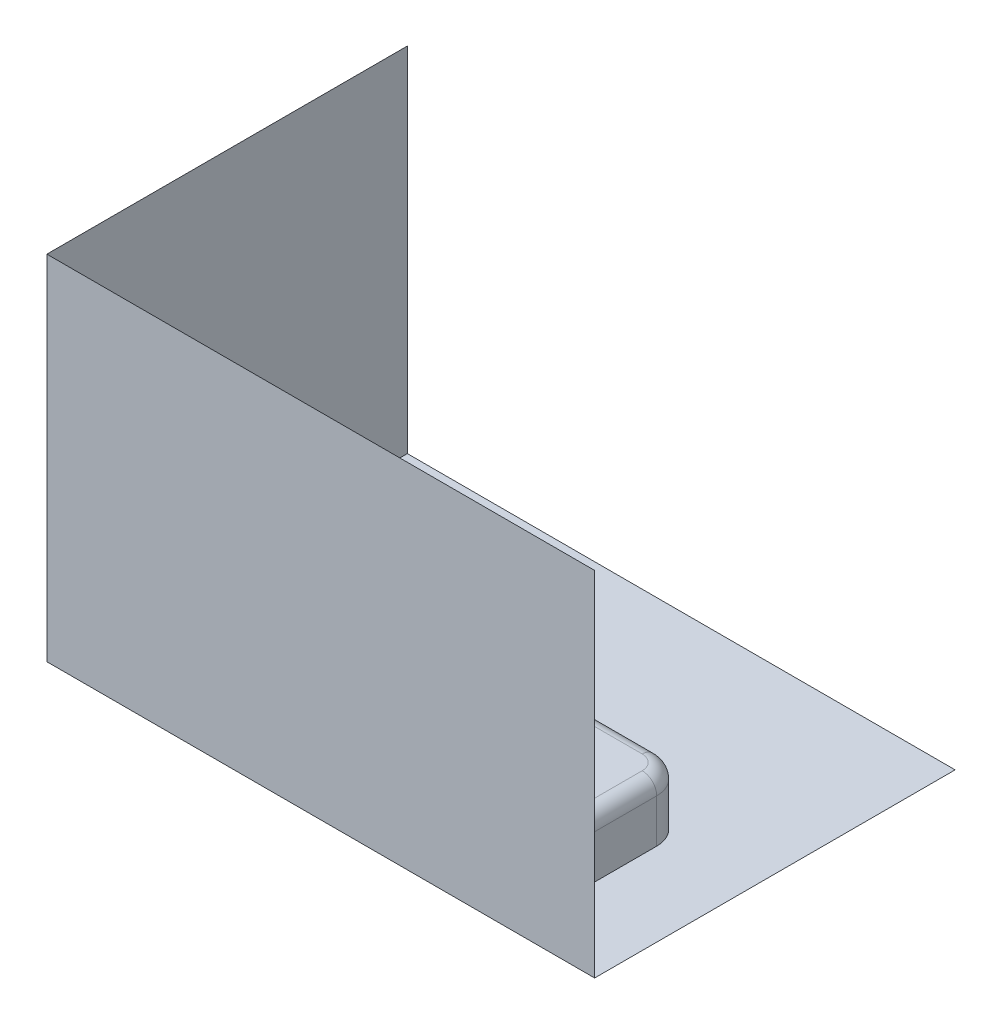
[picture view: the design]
ISO-10303-21;
HEADER;
FILE_DESCRIPTION(('STEP AP214'),'2;1');
FILE_NAME('part.step','',(''),(''),'','','');
FILE_SCHEMA(('AUTOMOTIVE_DESIGN { 1 0 10303 214 1 1 1 1 }'));
ENDSEC;
DATA;
#1=APPLICATION_CONTEXT('core data for automotive mechanical design processes');
#2=APPLICATION_PROTOCOL_DEFINITION('international standard','automotive_design',2000,#1);
#3=PRODUCT_CONTEXT('',#1,'mechanical');
#4=PRODUCT('Part','Part','',(#3));
#5=PRODUCT_RELATED_PRODUCT_CATEGORY('part','',(#4));
#6=PRODUCT_DEFINITION_FORMATION('','',#4);
#7=PRODUCT_DEFINITION_CONTEXT('part definition',#1,'design');
#8=PRODUCT_DEFINITION('design','',#6,#7);
#9=PRODUCT_DEFINITION_SHAPE('','',#8);
#10=(LENGTH_UNIT() NAMED_UNIT(*) SI_UNIT(.MILLI.,.METRE.));
#11=(NAMED_UNIT(*) PLANE_ANGLE_UNIT() SI_UNIT($,.RADIAN.));
#12=(NAMED_UNIT(*) SI_UNIT($,.STERADIAN.) SOLID_ANGLE_UNIT());
#13=UNCERTAINTY_MEASURE_WITH_UNIT(LENGTH_MEASURE(1.E-05),#10,'distance_accuracy_value','');
#14=(GEOMETRIC_REPRESENTATION_CONTEXT(3) GLOBAL_UNCERTAINTY_ASSIGNED_CONTEXT((#13)) GLOBAL_UNIT_ASSIGNED_CONTEXT((#10,
#11,#12)) REPRESENTATION_CONTEXT('',''));
#15=CARTESIAN_POINT('',(0.,0.,0.));
#16=DIRECTION('',(0.,0.,1.));
#17=DIRECTION('',(1.,0.,0.));
#18=AXIS2_PLACEMENT_3D('',#15,#16,#17);
#19=CARTESIAN_POINT('',(0.,0.,0.));
#20=DIRECTION('',(0.,-1.,0.));
#21=DIRECTION('',(0.,0.,-1.));
#22=AXIS2_PLACEMENT_3D('',#19,#20,#21);
#23=PLANE('',#22);
#24=DIRECTION('',(0.,0.,-1.));
#25=VECTOR('',#24,1.);
#26=CARTESIAN_POINT('',(0.,0.,0.));
#27=LINE('',#26,#25);
#28=CARTESIAN_POINT('',(0.,0.,0.));
#29=VERTEX_POINT('',#28);
#30=CARTESIAN_POINT('',(0.,0.,-78.8265915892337));
#31=VERTEX_POINT('',#30);
#32=EDGE_CURVE('E72',#29,#31,#27,.T.);
#33=ORIENTED_EDGE('',*,*,#32,.T.);
#34=DIRECTION('',(1.,0.,0.));
#35=VECTOR('',#34,1.);
#36=CARTESIAN_POINT('',(0.,0.,-78.8265915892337));
#37=LINE('',#36,#35);
#38=CARTESIAN_POINT('',(119.774346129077,0.,-78.8265915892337));
#39=VERTEX_POINT('',#38);
#40=EDGE_CURVE('E81',#31,#39,#37,.T.);
#41=ORIENTED_EDGE('',*,*,#40,.T.);
#42=DIRECTION('',(0.,0.,1.));
#43=VECTOR('',#42,1.);
#44=CARTESIAN_POINT('',(119.774346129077,0.,0.));
#45=LINE('',#44,#43);
#46=CARTESIAN_POINT('',(119.774346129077,0.,0.));
#47=VERTEX_POINT('',#46);
#48=EDGE_CURVE('E69',#39,#47,#45,.T.);
#49=ORIENTED_EDGE('',*,*,#48,.T.);
#50=DIRECTION('',(-1.,0.,0.));
#51=VECTOR('',#50,1.);
#52=CARTESIAN_POINT('',(0.,0.,0.));
#53=LINE('',#52,#51);
#54=EDGE_CURVE('E12',#47,#29,#53,.T.);
#55=ORIENTED_EDGE('',*,*,#54,.T.);
#56=EDGE_LOOP('',(#33,#41,#49,#55));
#57=FACE_BOUND('',#56,.T.);
#58=ADVANCED_FACE('F61',(#57),#23,.T.);
#59=OPEN_SHELL('',(#58));
#60=SHELL_BASED_SURFACE_MODEL('B2',(#59));
#61=CARTESIAN_POINT('',(0.,0.,-78.8265915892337));
#62=DIRECTION('',(-1.,0.,0.));
#63=DIRECTION('',(0.,0.,1.));
#64=AXIS2_PLACEMENT_3D('',#61,#62,#63);
#65=PLANE('',#64);
#66=DIRECTION('',(0.,-1.,0.));
#67=VECTOR('',#66,1.);
#68=CARTESIAN_POINT('',(0.,77.180854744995,-78.8265915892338));
#69=LINE('',#68,#67);
#70=CARTESIAN_POINT('',(0.,77.180854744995,-78.8265915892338));
#71=VERTEX_POINT('',#70);
#72=CARTESIAN_POINT('',(0.,0.,-78.8265915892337));
#73=VERTEX_POINT('',#72);
#74=EDGE_CURVE('E128',#71,#73,#69,.T.);
#75=ORIENTED_EDGE('',*,*,#74,.T.);
#76=DIRECTION('',(0.,0.,1.));
#77=VECTOR('',#76,1.);
#78=CARTESIAN_POINT('',(0.,0.,-78.8265915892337));
#79=LINE('',#78,#77);
#80=CARTESIAN_POINT('',(0.,0.,0.));
#81=VERTEX_POINT('',#80);
#82=EDGE_CURVE('E136',#73,#81,#79,.T.);
#83=ORIENTED_EDGE('',*,*,#82,.T.);
#84=DIRECTION('',(0.,1.,0.));
#85=VECTOR('',#84,1.);
#86=CARTESIAN_POINT('',(0.,77.180854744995,0.));
#87=LINE('',#86,#85);
#88=CARTESIAN_POINT('',(0.,77.180854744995,0.));
#89=VERTEX_POINT('',#88);
#90=EDGE_CURVE('E123',#81,#89,#87,.T.);
#91=ORIENTED_EDGE('',*,*,#90,.T.);
#92=DIRECTION('',(0.,0.,-1.));
#93=VECTOR('',#92,1.);
#94=CARTESIAN_POINT('',(0.,77.180854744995,-78.8265915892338));
#95=LINE('',#94,#93);
#96=EDGE_CURVE('E58',#89,#71,#95,.T.);
#97=ORIENTED_EDGE('',*,*,#96,.T.);
#98=EDGE_LOOP('',(#75,#83,#91,#97));
#99=FACE_BOUND('',#98,.T.);
#100=ADVANCED_FACE('F119',(#99),#65,.T.);
#101=OPEN_SHELL('',(#100));
#102=SHELL_BASED_SURFACE_MODEL('B6',(#101));
#103=CARTESIAN_POINT('',(0.,0.,0.));
#104=DIRECTION('',(0.,0.,1.));
#105=DIRECTION('',(1.,0.,0.));
#106=AXIS2_PLACEMENT_3D('',#103,#104,#105);
#107=PLANE('',#106);
#108=DIRECTION('',(0.,1.,0.));
#109=VECTOR('',#108,1.);
#110=CARTESIAN_POINT('',(0.,77.180854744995,0.));
#111=LINE('',#110,#109);
#112=CARTESIAN_POINT('',(0.,0.,0.));
#113=VERTEX_POINT('',#112);
#114=CARTESIAN_POINT('',(0.,77.180854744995,0.));
#115=VERTEX_POINT('',#114);
#116=EDGE_CURVE('E187',#113,#115,#111,.T.);
#117=ORIENTED_EDGE('',*,*,#116,.T.);
#118=DIRECTION('',(1.,0.,0.));
#119=VECTOR('',#118,1.);
#120=CARTESIAN_POINT('',(0.,77.180854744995,0.));
#121=LINE('',#120,#119);
#122=CARTESIAN_POINT('',(119.774346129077,77.180854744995,0.));
#123=VERTEX_POINT('',#122);
#124=EDGE_CURVE('E199',#115,#123,#121,.T.);
#125=ORIENTED_EDGE('',*,*,#124,.T.);
#126=DIRECTION('',(0.,-1.,0.));
#127=VECTOR('',#126,1.);
#128=CARTESIAN_POINT('',(119.774346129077,77.180854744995,0.));
#129=LINE('',#128,#127);
#130=CARTESIAN_POINT('',(119.774346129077,0.,0.));
#131=VERTEX_POINT('',#130);
#132=EDGE_CURVE('E185',#123,#131,#129,.T.);
#133=ORIENTED_EDGE('',*,*,#132,.T.);
#134=DIRECTION('',(-1.,0.,0.));
#135=VECTOR('',#134,1.);
#136=CARTESIAN_POINT('',(0.,0.,0.));
#137=LINE('',#136,#135);
#138=EDGE_CURVE('E117',#131,#113,#137,.T.);
#139=ORIENTED_EDGE('',*,*,#138,.T.);
#140=EDGE_LOOP('',(#117,#125,#133,#139));
#141=FACE_BOUND('',#140,.T.);
#142=ADVANCED_FACE('F180',(#141),#107,.F.);
#143=OPEN_SHELL('',(#142));
#144=SHELL_BASED_SURFACE_MODEL('B53',(#143));
#145=CARTESIAN_POINT('',(0.,0.,-38.1));
#146=DIRECTION('',(0.,-1.,0.));
#147=DIRECTION('',(0.,0.,-1.));
#148=AXIS2_PLACEMENT_3D('',#145,#146,#147);
#149=PLANE('',#148);
#150=CARTESIAN_POINT('',(12.7,0.,-25.4));
#151=DIRECTION('',(0.,1.,0.));
#152=DIRECTION('',(0.,0.,1.));
#153=AXIS2_PLACEMENT_3D('',#150,#151,#152);
#154=CIRCLE('',#153,3.571875);
#155=CARTESIAN_POINT('',(12.7,0.,-21.828125));
#156=VERTEX_POINT('',#155);
#157=EDGE_CURVE('E666',#156,#156,#154,.T.);
#158=ORIENTED_EDGE('',*,*,#157,.T.);
#159=EDGE_LOOP('',(#158));
#160=FACE_BOUND('',#159,.T.);
#161=DIRECTION('',(1.,0.,0.));
#162=VECTOR('',#161,1.);
#163=CARTESIAN_POINT('',(0.,0.,0.));
#164=LINE('',#163,#162);
#165=CARTESIAN_POINT('',(6.35,0.,0.));
#166=VERTEX_POINT('',#165);
#167=CARTESIAN_POINT('',(31.75,0.,-2.27373675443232E-10));
#168=VERTEX_POINT('',#167);
#169=EDGE_CURVE('E463',#166,#168,#164,.T.);
#170=ORIENTED_EDGE('',*,*,#169,.F.);
#171=CARTESIAN_POINT('',(6.35,0.,-6.35));
#172=DIRECTION('',(0.,-1.,0.));
#173=DIRECTION('',(0.,0.,-1.));
#174=AXIS2_PLACEMENT_3D('',#171,#172,#173);
#175=CIRCLE('',#174,6.35);
#176=CARTESIAN_POINT('',(0.,0.,-6.35));
#177=VERTEX_POINT('',#176);
#178=EDGE_CURVE('E477',#166,#177,#175,.T.);
#179=ORIENTED_EDGE('',*,*,#178,.T.);
#180=DIRECTION('',(0.,0.,1.));
#181=VECTOR('',#180,1.);
#182=CARTESIAN_POINT('',(0.,0.,0.));
#183=LINE('',#182,#181);
#184=CARTESIAN_POINT('',(0.,0.,-31.75));
#185=VERTEX_POINT('',#184);
#186=EDGE_CURVE('E459',#185,#177,#183,.T.);
#187=ORIENTED_EDGE('',*,*,#186,.F.);
#188=CARTESIAN_POINT('',(6.35,0.,-31.75));
#189=DIRECTION('',(0.,-1.,0.));
#190=DIRECTION('',(0.,0.,-1.));
#191=AXIS2_PLACEMENT_3D('',#188,#189,#190);
#192=CIRCLE('',#191,6.35);
#193=CARTESIAN_POINT('',(6.35,0.,-38.1));
#194=VERTEX_POINT('',#193);
#195=EDGE_CURVE('E427',#185,#194,#192,.T.);
#196=ORIENTED_EDGE('',*,*,#195,.T.);
#197=DIRECTION('',(-1.,0.,0.));
#198=VECTOR('',#197,1.);
#199=CARTESIAN_POINT('',(0.,0.,-38.1));
#200=LINE('',#199,#198);
#201=CARTESIAN_POINT('',(31.75,0.,-38.1));
#202=VERTEX_POINT('',#201);
#203=EDGE_CURVE('E414',#202,#194,#200,.T.);
#204=ORIENTED_EDGE('',*,*,#203,.F.);
#205=DIRECTION('',(0.,0.,1.));
#206=VECTOR('',#205,1.);
#207=CARTESIAN_POINT('',(31.75,0.,-38.1));
#208=LINE('',#207,#206);
#209=EDGE_CURVE('E430',#202,#168,#208,.T.);
#210=ORIENTED_EDGE('',*,*,#209,.T.);
#211=EDGE_LOOP('',(#170,#179,#187,#196,#204,#210));
#212=FACE_BOUND('',#211,.T.);
#213=ADVANCED_FACE('F225',(#160,#212),#149,.T.);
#214=CARTESIAN_POINT('',(0.,12.7,0.));
#215=DIRECTION('',(1.,0.,0.));
#216=DIRECTION('',(0.,0.,-1.));
#217=AXIS2_PLACEMENT_3D('',#214,#215,#216);
#218=PLANE('',#217);
#219=DIRECTION('',(0.,-1.,0.));
#220=VECTOR('',#219,1.);
#221=CARTESIAN_POINT('',(0.,12.7,-6.35));
#222=LINE('',#221,#220);
#223=CARTESIAN_POINT('',(0.,9.525,-6.35));
#224=VERTEX_POINT('',#223);
#225=EDGE_CURVE('E483',#177,#224,#222,.F.);
#226=ORIENTED_EDGE('',*,*,#225,.T.);
#227=DIRECTION('',(0.,0.,1.));
#228=VECTOR('',#227,1.);
#229=CARTESIAN_POINT('',(0.,9.525,0.));
#230=LINE('',#229,#228);
#231=CARTESIAN_POINT('',(0.,9.525,-31.75));
#232=VERTEX_POINT('',#231);
#233=EDGE_CURVE('E579',#224,#232,#230,.F.);
#234=ORIENTED_EDGE('',*,*,#233,.T.);
#235=DIRECTION('',(0.,-1.,0.));
#236=VECTOR('',#235,1.);
#237=CARTESIAN_POINT('',(0.,12.7,-31.75));
#238=LINE('',#237,#236);
#239=EDGE_CURVE('E482',#232,#185,#238,.T.);
#240=ORIENTED_EDGE('',*,*,#239,.T.);
#241=ORIENTED_EDGE('',*,*,#186,.T.);
#242=EDGE_LOOP('',(#226,#234,#240,#241));
#243=FACE_BOUND('',#242,.T.);
#244=ADVANCED_FACE('F686',(#243),#218,.F.);
#245=CARTESIAN_POINT('',(0.,12.7,0.));
#246=DIRECTION('',(0.,0.,-1.));
#247=DIRECTION('',(-1.,0.,0.));
#248=AXIS2_PLACEMENT_3D('',#245,#246,#247);
#249=PLANE('',#248);
#250=CARTESIAN_POINT('',(50.8,38.1,-1.13686837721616E-10));
#251=DIRECTION('',(0.,0.,1.));
#252=DIRECTION('',(1.,0.,0.));
#253=AXIS2_PLACEMENT_3D('',#250,#251,#252);
#254=CIRCLE('',#253,9.52499999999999);
#255=CARTESIAN_POINT('',(60.325,38.1,-1.13686837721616E-10));
#256=VERTEX_POINT('',#255);
#257=EDGE_CURVE('E448',#256,#256,#254,.T.);
#258=ORIENTED_EDGE('',*,*,#257,.F.);
#259=EDGE_LOOP('',(#258));
#260=FACE_BOUND('',#259,.T.);
#261=DIRECTION('',(0.,-1.,0.));
#262=VECTOR('',#261,1.);
#263=CARTESIAN_POINT('',(95.25,12.7,0.));
#264=LINE('',#263,#262);
#265=CARTESIAN_POINT('',(95.25,0.,0.));
#266=VERTEX_POINT('',#265);
#267=CARTESIAN_POINT('',(95.25,9.525,0.));
#268=VERTEX_POINT('',#267);
#269=EDGE_CURVE('E473',#266,#268,#264,.F.);
#270=ORIENTED_EDGE('',*,*,#269,.T.);
#271=DIRECTION('',(1.,0.,0.));
#272=VECTOR('',#271,1.);
#273=CARTESIAN_POINT('',(0.,9.525,0.));
#274=LINE('',#273,#272);
#275=CARTESIAN_POINT('',(73.025,9.525,0.));
#276=VERTEX_POINT('',#275);
#277=EDGE_CURVE('E577',#268,#276,#274,.F.);
#278=ORIENTED_EDGE('',*,*,#277,.T.);
#279=CARTESIAN_POINT('',(73.025,15.875,0.));
#280=DIRECTION('',(0.,0.,-1.));
#281=DIRECTION('',(-1.,0.,0.));
#282=AXIS2_PLACEMENT_3D('',#279,#280,#281);
#283=CIRCLE('',#282,6.35);
#284=CARTESIAN_POINT('',(66.675,15.875,0.));
#285=VERTEX_POINT('',#284);
#286=EDGE_CURVE('E572',#285,#276,#283,.F.);
#287=ORIENTED_EDGE('',*,*,#286,.F.);
#288=DIRECTION('',(0.,1.,0.));
#289=VECTOR('',#288,1.);
#290=CARTESIAN_POINT('',(66.675,38.1,0.));
#291=LINE('',#290,#289);
#292=CARTESIAN_POINT('',(66.675,38.1,0.));
#293=VERTEX_POINT('',#292);
#294=EDGE_CURVE('E571',#285,#293,#291,.T.);
#295=ORIENTED_EDGE('',*,*,#294,.T.);
#296=CARTESIAN_POINT('',(50.8,38.1,0.));
#297=DIRECTION('',(0.,0.,-1.));
#298=DIRECTION('',(-1.,0.,0.));
#299=AXIS2_PLACEMENT_3D('',#296,#297,#298);
#300=CIRCLE('',#299,15.875);
#301=CARTESIAN_POINT('',(34.925,38.1,0.));
#302=VERTEX_POINT('',#301);
#303=EDGE_CURVE('E567',#293,#302,#300,.F.);
#304=ORIENTED_EDGE('',*,*,#303,.T.);
#305=DIRECTION('',(0.,-1.,0.));
#306=VECTOR('',#305,1.);
#307=CARTESIAN_POINT('',(34.925,12.7,0.));
#308=LINE('',#307,#306);
#309=CARTESIAN_POINT('',(34.925,15.875,0.));
#310=VERTEX_POINT('',#309);
#311=EDGE_CURVE('E570',#302,#310,#308,.T.);
#312=ORIENTED_EDGE('',*,*,#311,.T.);
#313=CARTESIAN_POINT('',(28.575,15.875,0.));
#314=DIRECTION('',(0.,0.,-1.));
#315=DIRECTION('',(-1.,0.,0.));
#316=AXIS2_PLACEMENT_3D('',#313,#314,#315);
#317=CIRCLE('',#316,6.35);
#318=CARTESIAN_POINT('',(28.575,9.525,0.));
#319=VERTEX_POINT('',#318);
#320=EDGE_CURVE('E562',#319,#310,#317,.F.);
#321=ORIENTED_EDGE('',*,*,#320,.F.);
#322=DIRECTION('',(1.,0.,0.));
#323=VECTOR('',#322,1.);
#324=CARTESIAN_POINT('',(0.,9.525,0.));
#325=LINE('',#324,#323);
#326=CARTESIAN_POINT('',(6.35,9.525,0.));
#327=VERTEX_POINT('',#326);
#328=EDGE_CURVE('E565',#319,#327,#325,.F.);
#329=ORIENTED_EDGE('',*,*,#328,.T.);
#330=DIRECTION('',(0.,-1.,0.));
#331=VECTOR('',#330,1.);
#332=CARTESIAN_POINT('',(6.35,12.7,0.));
#333=LINE('',#332,#331);
#334=EDGE_CURVE('E480',#327,#166,#333,.T.);
#335=ORIENTED_EDGE('',*,*,#334,.T.);
#336=ORIENTED_EDGE('',*,*,#169,.T.);
#337=CARTESIAN_POINT('',(37.2492613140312,-3.17500000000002,0.));
#338=DIRECTION('',(0.,0.,-1.));
#339=DIRECTION('',(-1.,0.,0.));
#340=AXIS2_PLACEMENT_3D('',#337,#338,#339);
#341=CIRCLE('',#340,6.35);
#342=CARTESIAN_POINT('',(37.2492613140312,3.17499999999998,-2.27373675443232E-10));
#343=VERTEX_POINT('',#342);
#344=EDGE_CURVE('E422',#168,#343,#341,.T.);
#345=ORIENTED_EDGE('',*,*,#344,.T.);
#346=DIRECTION('',(-1.,0.,0.));
#347=VECTOR('',#346,1.);
#348=CARTESIAN_POINT('',(31.75,3.17499999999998,-2.27373675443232E-10));
#349=LINE('',#348,#347);
#350=CARTESIAN_POINT('',(64.3507386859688,3.17499999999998,-2.27373675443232E-10));
#351=VERTEX_POINT('',#350);
#352=EDGE_CURVE('E441',#351,#343,#349,.T.);
#353=ORIENTED_EDGE('',*,*,#352,.F.);
#354=CARTESIAN_POINT('',(64.3507386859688,-3.17500000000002,0.));
#355=DIRECTION('',(0.,0.,-1.));
#356=DIRECTION('',(-1.,0.,0.));
#357=AXIS2_PLACEMENT_3D('',#354,#355,#356);
#358=CIRCLE('',#357,6.35);
#359=CARTESIAN_POINT('',(69.85,0.,-2.27373675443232E-10));
#360=VERTEX_POINT('',#359);
#361=EDGE_CURVE('E499',#351,#360,#358,.T.);
#362=ORIENTED_EDGE('',*,*,#361,.T.);
#363=EDGE_CURVE('E465',#360,#266,#164,.T.);
#364=ORIENTED_EDGE('',*,*,#363,.T.);
#365=EDGE_LOOP('',(#270,#278,#287,#295,#304,#312,#321,#329,#335,#336,#345,#353,#362,#364));
#366=FACE_BOUND('',#365,.T.);
#367=ADVANCED_FACE('F680',(#260,#366),#249,.F.);
#368=CARTESIAN_POINT('',(101.6,12.7,0.));
#369=DIRECTION('',(-1.,0.,0.));
#370=DIRECTION('',(0.,0.,1.));
#371=AXIS2_PLACEMENT_3D('',#368,#369,#370);
#372=PLANE('',#371);
#373=DIRECTION('',(0.,-1.,0.));
#374=VECTOR('',#373,1.);
#375=CARTESIAN_POINT('',(101.6,12.7,-31.75));
#376=LINE('',#375,#374);
#377=CARTESIAN_POINT('',(101.6,0.,-31.75));
#378=VERTEX_POINT('',#377);
#379=CARTESIAN_POINT('',(101.6,9.525,-31.75));
#380=VERTEX_POINT('',#379);
#381=EDGE_CURVE('E487',#378,#380,#376,.F.);
#382=ORIENTED_EDGE('',*,*,#381,.T.);
#383=DIRECTION('',(0.,0.,-1.));
#384=VECTOR('',#383,1.);
#385=CARTESIAN_POINT('',(101.6,9.525,0.));
#386=LINE('',#385,#384);
#387=CARTESIAN_POINT('',(101.6,9.525,-6.35));
#388=VERTEX_POINT('',#387);
#389=EDGE_CURVE('E547',#380,#388,#386,.F.);
#390=ORIENTED_EDGE('',*,*,#389,.T.);
#391=DIRECTION('',(0.,-1.,0.));
#392=VECTOR('',#391,1.);
#393=CARTESIAN_POINT('',(101.6,12.7,-6.35));
#394=LINE('',#393,#392);
#395=CARTESIAN_POINT('',(101.6,0.,-6.35));
#396=VERTEX_POINT('',#395);
#397=EDGE_CURVE('E489',#388,#396,#394,.T.);
#398=ORIENTED_EDGE('',*,*,#397,.T.);
#399=DIRECTION('',(0.,0.,-1.));
#400=VECTOR('',#399,1.);
#401=CARTESIAN_POINT('',(101.6,0.,0.));
#402=LINE('',#401,#400);
#403=EDGE_CURVE('E435',#396,#378,#402,.T.);
#404=ORIENTED_EDGE('',*,*,#403,.T.);
#405=EDGE_LOOP('',(#382,#390,#398,#404));
#406=FACE_BOUND('',#405,.T.);
#407=ADVANCED_FACE('F727',(#406),#372,.F.);
#408=CARTESIAN_POINT('',(0.,12.7,-38.1));
#409=DIRECTION('',(0.,0.,1.));
#410=DIRECTION('',(1.,0.,0.));
#411=AXIS2_PLACEMENT_3D('',#408,#409,#410);
#412=PLANE('',#411);
#413=DIRECTION('',(0.,-1.,0.));
#414=VECTOR('',#413,1.);
#415=CARTESIAN_POINT('',(6.35,12.7,-38.1));
#416=LINE('',#415,#414);
#417=CARTESIAN_POINT('',(6.35,9.525,-38.1));
#418=VERTEX_POINT('',#417);
#419=EDGE_CURVE('E496',#194,#418,#416,.F.);
#420=ORIENTED_EDGE('',*,*,#419,.T.);
#421=DIRECTION('',(-1.,0.,0.));
#422=VECTOR('',#421,1.);
#423=CARTESIAN_POINT('',(0.,9.525,-38.1));
#424=LINE('',#423,#422);
#425=CARTESIAN_POINT('',(95.25,9.525,-38.1));
#426=VERTEX_POINT('',#425);
#427=EDGE_CURVE('E540',#418,#426,#424,.F.);
#428=ORIENTED_EDGE('',*,*,#427,.T.);
#429=DIRECTION('',(0.,-1.,0.));
#430=VECTOR('',#429,1.);
#431=CARTESIAN_POINT('',(95.25,12.7,-38.1));
#432=LINE('',#431,#430);
#433=CARTESIAN_POINT('',(95.25,0.,-38.1));
#434=VERTEX_POINT('',#433);
#435=EDGE_CURVE('E498',#426,#434,#432,.T.);
#436=ORIENTED_EDGE('',*,*,#435,.T.);
#437=CARTESIAN_POINT('',(69.85,0.,-38.1));
#438=VERTEX_POINT('',#437);
#439=EDGE_CURVE('E431',#434,#438,#200,.T.);
#440=ORIENTED_EDGE('',*,*,#439,.T.);
#441=CARTESIAN_POINT('',(64.3507386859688,-3.17500000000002,-38.1));
#442=DIRECTION('',(0.,0.,1.));
#443=DIRECTION('',(1.,0.,0.));
#444=AXIS2_PLACEMENT_3D('',#441,#442,#443);
#445=CIRCLE('',#444,6.35);
#446=CARTESIAN_POINT('',(64.3507386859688,3.17499999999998,-38.1));
#447=VERTEX_POINT('',#446);
#448=EDGE_CURVE('E505',#438,#447,#445,.T.);
#449=ORIENTED_EDGE('',*,*,#448,.T.);
#450=DIRECTION('',(-1.,0.,0.));
#451=VECTOR('',#450,1.);
#452=CARTESIAN_POINT('',(31.75,3.17499999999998,-38.1));
#453=LINE('',#452,#451);
#454=CARTESIAN_POINT('',(37.2492613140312,3.17499999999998,-38.1));
#455=VERTEX_POINT('',#454);
#456=EDGE_CURVE('E417',#447,#455,#453,.T.);
#457=ORIENTED_EDGE('',*,*,#456,.T.);
#458=CARTESIAN_POINT('',(37.2492613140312,-3.17500000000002,-38.1));
#459=DIRECTION('',(0.,0.,1.));
#460=DIRECTION('',(1.,0.,0.));
#461=AXIS2_PLACEMENT_3D('',#458,#459,#460);
#462=CIRCLE('',#461,6.35);
#463=EDGE_CURVE('E407',#455,#202,#462,.T.);
#464=ORIENTED_EDGE('',*,*,#463,.T.);
#465=ORIENTED_EDGE('',*,*,#203,.T.);
#466=EDGE_LOOP('',(#420,#428,#436,#440,#449,#457,#464,#465));
#467=FACE_BOUND('',#466,.T.);
#468=ADVANCED_FACE('F411',(#467),#412,.F.);
#469=CARTESIAN_POINT('',(0.,12.7,-38.1));
#470=DIRECTION('',(0.,-1.,0.));
#471=DIRECTION('',(0.,0.,-1.));
#472=AXIS2_PLACEMENT_3D('',#469,#470,#471);
#473=PLANE('',#472);
#474=CARTESIAN_POINT('',(66.675,12.7,-9.525));
#475=DIRECTION('',(0.,-1.,0.));
#476=DIRECTION('',(0.,0.,-1.));
#477=AXIS2_PLACEMENT_3D('',#474,#475,#476);
#478=CIRCLE('',#477,6.35);
#479=CARTESIAN_POINT('',(73.025,12.7,-9.525));
#480=VERTEX_POINT('',#479);
#481=CARTESIAN_POINT('',(66.675,12.7,-15.875));
#482=VERTEX_POINT('',#481);
#483=EDGE_CURVE('E526',#480,#482,#478,.F.);
#484=ORIENTED_EDGE('',*,*,#483,.F.);
#485=DIRECTION('',(0.,0.,1.));
#486=VECTOR('',#485,1.);
#487=CARTESIAN_POINT('',(73.025,12.7,-38.1));
#488=LINE('',#487,#486);
#489=CARTESIAN_POINT('',(73.025,12.7,-3.175));
#490=VERTEX_POINT('',#489);
#491=EDGE_CURVE('E531',#480,#490,#488,.T.);
#492=ORIENTED_EDGE('',*,*,#491,.T.);
#493=DIRECTION('',(1.,0.,0.));
#494=VECTOR('',#493,1.);
#495=CARTESIAN_POINT('',(0.,12.7,-3.175));
#496=LINE('',#495,#494);
#497=CARTESIAN_POINT('',(95.25,12.7,-3.175));
#498=VERTEX_POINT('',#497);
#499=EDGE_CURVE('E528',#490,#498,#496,.T.);
#500=ORIENTED_EDGE('',*,*,#499,.T.);
#501=CARTESIAN_POINT('',(95.25,12.7,-6.35));
#502=DIRECTION('',(0.,-1.,0.));
#503=DIRECTION('',(0.,0.,-1.));
#504=AXIS2_PLACEMENT_3D('',#501,#502,#503);
#505=CIRCLE('',#504,3.175);
#506=CARTESIAN_POINT('',(98.425,12.7,-6.35));
#507=VERTEX_POINT('',#506);
#508=EDGE_CURVE('E527',#498,#507,#505,.F.);
#509=ORIENTED_EDGE('',*,*,#508,.T.);
#510=DIRECTION('',(0.,0.,-1.));
#511=VECTOR('',#510,1.);
#512=CARTESIAN_POINT('',(98.425,12.7,-38.1));
#513=LINE('',#512,#511);
#514=CARTESIAN_POINT('',(98.425,12.7,-31.75));
#515=VERTEX_POINT('',#514);
#516=EDGE_CURVE('E518',#507,#515,#513,.T.);
#517=ORIENTED_EDGE('',*,*,#516,.T.);
#518=CARTESIAN_POINT('',(95.25,12.7,-31.75));
#519=DIRECTION('',(0.,-1.,0.));
#520=DIRECTION('',(0.,0.,-1.));
#521=AXIS2_PLACEMENT_3D('',#518,#519,#520);
#522=CIRCLE('',#521,3.175);
#523=CARTESIAN_POINT('',(95.25,12.7,-34.925));
#524=VERTEX_POINT('',#523);
#525=EDGE_CURVE('E519',#515,#524,#522,.F.);
#526=ORIENTED_EDGE('',*,*,#525,.T.);
#527=DIRECTION('',(-1.,0.,0.));
#528=VECTOR('',#527,1.);
#529=CARTESIAN_POINT('',(0.,12.7,-34.925));
#530=LINE('',#529,#528);
#531=CARTESIAN_POINT('',(6.35,12.7,-34.925));
#532=VERTEX_POINT('',#531);
#533=EDGE_CURVE('E511',#524,#532,#530,.T.);
#534=ORIENTED_EDGE('',*,*,#533,.T.);
#535=CARTESIAN_POINT('',(6.35,12.7,-31.75));
#536=DIRECTION('',(0.,-1.,0.));
#537=DIRECTION('',(0.,0.,-1.));
#538=AXIS2_PLACEMENT_3D('',#535,#536,#537);
#539=CIRCLE('',#538,3.175);
#540=CARTESIAN_POINT('',(3.175,12.7,-31.75));
#541=VERTEX_POINT('',#540);
#542=EDGE_CURVE('E509',#532,#541,#539,.F.);
#543=ORIENTED_EDGE('',*,*,#542,.T.);
#544=DIRECTION('',(0.,0.,1.));
#545=VECTOR('',#544,1.);
#546=CARTESIAN_POINT('',(3.175,12.7,-38.1));
#547=LINE('',#546,#545);
#548=CARTESIAN_POINT('',(3.175,12.7,-6.35));
#549=VERTEX_POINT('',#548);
#550=EDGE_CURVE('E507',#541,#549,#547,.T.);
#551=ORIENTED_EDGE('',*,*,#550,.T.);
#552=CARTESIAN_POINT('',(6.35,12.7,-6.35));
#553=DIRECTION('',(0.,-1.,0.));
#554=DIRECTION('',(0.,0.,-1.));
#555=AXIS2_PLACEMENT_3D('',#552,#553,#554);
#556=CIRCLE('',#555,3.175);
#557=CARTESIAN_POINT('',(6.35,12.7,-3.175));
#558=VERTEX_POINT('',#557);
#559=EDGE_CURVE('E506',#549,#558,#556,.F.);
#560=ORIENTED_EDGE('',*,*,#559,.T.);
#561=DIRECTION('',(1.,0.,0.));
#562=VECTOR('',#561,1.);
#563=CARTESIAN_POINT('',(0.,12.7,-3.175));
#564=LINE('',#563,#562);
#565=CARTESIAN_POINT('',(28.575,12.7,-3.175));
#566=VERTEX_POINT('',#565);
#567=EDGE_CURVE('E423',#558,#566,#564,.T.);
#568=ORIENTED_EDGE('',*,*,#567,.T.);
#569=DIRECTION('',(0.,0.,-1.));
#570=VECTOR('',#569,1.);
#571=CARTESIAN_POINT('',(28.575,12.7,-38.1));
#572=LINE('',#571,#570);
#573=CARTESIAN_POINT('',(28.575,12.7,-9.525));
#574=VERTEX_POINT('',#573);
#575=EDGE_CURVE('E515',#566,#574,#572,.T.);
#576=ORIENTED_EDGE('',*,*,#575,.T.);
#577=CARTESIAN_POINT('',(34.925,12.7,-9.525));
#578=DIRECTION('',(0.,-1.,0.));
#579=DIRECTION('',(0.,0.,-1.));
#580=AXIS2_PLACEMENT_3D('',#577,#578,#579);
#581=CIRCLE('',#580,6.35);
#582=CARTESIAN_POINT('',(34.925,12.7,-15.875));
#583=VERTEX_POINT('',#582);
#584=EDGE_CURVE('E522',#583,#574,#581,.F.);
#585=ORIENTED_EDGE('',*,*,#584,.F.);
#586=DIRECTION('',(1.,0.,0.));
#587=VECTOR('',#586,1.);
#588=CARTESIAN_POINT('',(0.,12.7,-15.875));
#589=LINE('',#588,#587);
#590=EDGE_CURVE('E521',#583,#482,#589,.T.);
#591=ORIENTED_EDGE('',*,*,#590,.T.);
#592=EDGE_LOOP('',(#484,#492,#500,#509,#517,#526,#534,#543,#551,#560,#568,#576,#585,#591));
#593=FACE_BOUND('',#592,.T.);
#594=CARTESIAN_POINT('',(88.9,12.6999999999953,-25.4));
#595=DIRECTION('',(0.,1.,0.));
#596=DIRECTION('',(0.,0.,1.));
#597=AXIS2_PLACEMENT_3D('',#594,#595,#596);
#598=CIRCLE('',#597,3.57187499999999);
#599=CARTESIAN_POINT('',(88.9,12.6999999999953,-21.828125));
#600=VERTEX_POINT('',#599);
#601=EDGE_CURVE('E665',#600,#600,#598,.T.);
#602=ORIENTED_EDGE('',*,*,#601,.F.);
#603=EDGE_LOOP('',(#602));
#604=FACE_BOUND('',#603,.T.);
#605=CARTESIAN_POINT('',(12.7,12.6999999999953,-25.4));
#606=DIRECTION('',(0.,1.,0.));
#607=DIRECTION('',(0.,0.,1.));
#608=AXIS2_PLACEMENT_3D('',#605,#606,#607);
#609=CIRCLE('',#608,3.57187499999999);
#610=CARTESIAN_POINT('',(12.7,12.6999999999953,-21.828125));
#611=VERTEX_POINT('',#610);
#612=EDGE_CURVE('E675',#611,#611,#609,.T.);
#613=ORIENTED_EDGE('',*,*,#612,.F.);
#614=EDGE_LOOP('',(#613));
#615=FACE_BOUND('',#614,.T.);
#616=ADVANCED_FACE('F759',(#593,#604,#615),#473,.F.);
#617=CARTESIAN_POINT('',(88.9,0.,-25.4));
#618=DIRECTION('',(0.,1.,0.));
#619=DIRECTION('',(0.,0.,1.));
#620=AXIS2_PLACEMENT_3D('',#617,#618,#619);
#621=CIRCLE('',#620,3.571875);
#622=CARTESIAN_POINT('',(88.9,0.,-21.828125));
#623=VERTEX_POINT('',#622);
#624=EDGE_CURVE('E660',#623,#623,#621,.T.);
#625=ORIENTED_EDGE('',*,*,#624,.T.);
#626=EDGE_LOOP('',(#625));
#627=FACE_BOUND('',#626,.T.);
#628=ORIENTED_EDGE('',*,*,#403,.F.);
#629=CARTESIAN_POINT('',(95.25,0.,-6.35));
#630=DIRECTION('',(0.,-1.,0.));
#631=DIRECTION('',(0.,0.,-1.));
#632=AXIS2_PLACEMENT_3D('',#629,#630,#631);
#633=CIRCLE('',#632,6.35);
#634=EDGE_CURVE('E494',#396,#266,#633,.T.);
#635=ORIENTED_EDGE('',*,*,#634,.T.);
#636=ORIENTED_EDGE('',*,*,#363,.F.);
#637=DIRECTION('',(0.,0.,1.));
#638=VECTOR('',#637,1.);
#639=CARTESIAN_POINT('',(69.85,0.,-38.1));
#640=LINE('',#639,#638);
#641=EDGE_CURVE('E436',#438,#360,#640,.T.);
#642=ORIENTED_EDGE('',*,*,#641,.F.);
#643=ORIENTED_EDGE('',*,*,#439,.F.);
#644=CARTESIAN_POINT('',(95.25,0.,-31.75));
#645=DIRECTION('',(0.,-1.,0.));
#646=DIRECTION('',(0.,0.,-1.));
#647=AXIS2_PLACEMENT_3D('',#644,#645,#646);
#648=CIRCLE('',#647,6.35);
#649=EDGE_CURVE('E495',#434,#378,#648,.T.);
#650=ORIENTED_EDGE('',*,*,#649,.T.);
#651=EDGE_LOOP('',(#628,#635,#636,#642,#643,#650));
#652=FACE_BOUND('',#651,.T.);
#653=ADVANCED_FACE('F734',(#627,#652),#149,.T.);
#654=CARTESIAN_POINT('',(31.75,0.,-12.7));
#655=DIRECTION('',(-1.,0.,0.));
#656=DIRECTION('',(0.,0.,1.));
#657=AXIS2_PLACEMENT_3D('',#654,#655,#656);
#658=PLANE('',#657);
#659=DIRECTION('',(0.,0.,1.));
#660=VECTOR('',#659,1.);
#661=CARTESIAN_POINT('',(31.75,38.1,-12.7));
#662=LINE('',#661,#660);
#663=CARTESIAN_POINT('',(31.75,38.1,-9.525));
#664=VERTEX_POINT('',#663);
#665=CARTESIAN_POINT('',(31.75,38.1,-3.175));
#666=VERTEX_POINT('',#665);
#667=EDGE_CURVE('E453',#664,#666,#662,.T.);
#668=ORIENTED_EDGE('',*,*,#667,.F.);
#669=DIRECTION('',(0.,-1.,0.));
#670=VECTOR('',#669,1.);
#671=CARTESIAN_POINT('',(31.75,0.,-9.525));
#672=LINE('',#671,#670);
#673=CARTESIAN_POINT('',(31.75,15.875,-9.525));
#674=VERTEX_POINT('',#673);
#675=EDGE_CURVE('E542',#664,#674,#672,.T.);
#676=ORIENTED_EDGE('',*,*,#675,.T.);
#677=DIRECTION('',(0.,0.,-1.));
#678=VECTOR('',#677,1.);
#679=CARTESIAN_POINT('',(31.75,15.875,-12.7));
#680=LINE('',#679,#678);
#681=CARTESIAN_POINT('',(31.75,15.875,-3.175));
#682=VERTEX_POINT('',#681);
#683=EDGE_CURVE('E545',#674,#682,#680,.F.);
#684=ORIENTED_EDGE('',*,*,#683,.T.);
#685=DIRECTION('',(0.,-1.,0.));
#686=VECTOR('',#685,1.);
#687=CARTESIAN_POINT('',(31.75,38.1,-3.175));
#688=LINE('',#687,#686);
#689=EDGE_CURVE('E537',#682,#666,#688,.F.);
#690=ORIENTED_EDGE('',*,*,#689,.T.);
#691=EDGE_LOOP('',(#668,#676,#684,#690));
#692=FACE_BOUND('',#691,.T.);
#693=ADVANCED_FACE('F757',(#692),#658,.T.);
#694=CARTESIAN_POINT('',(69.85,38.1,-12.7));
#695=DIRECTION('',(1.,0.,0.));
#696=DIRECTION('',(0.,0.,-1.));
#697=AXIS2_PLACEMENT_3D('',#694,#695,#696);
#698=PLANE('',#697);
#699=DIRECTION('',(0.,0.,1.));
#700=VECTOR('',#699,1.);
#701=CARTESIAN_POINT('',(69.85,15.875,-12.7));
#702=LINE('',#701,#700);
#703=CARTESIAN_POINT('',(69.85,15.875,-3.175));
#704=VERTEX_POINT('',#703);
#705=CARTESIAN_POINT('',(69.85,15.875,-9.525));
#706=VERTEX_POINT('',#705);
#707=EDGE_CURVE('E234',#704,#706,#702,.F.);
#708=ORIENTED_EDGE('',*,*,#707,.T.);
#709=DIRECTION('',(0.,1.,0.));
#710=VECTOR('',#709,1.);
#711=CARTESIAN_POINT('',(69.85,38.1,-9.525));
#712=LINE('',#711,#710);
#713=CARTESIAN_POINT('',(69.85,38.1,-9.525));
#714=VERTEX_POINT('',#713);
#715=EDGE_CURVE('E174',#706,#714,#712,.T.);
#716=ORIENTED_EDGE('',*,*,#715,.T.);
#717=DIRECTION('',(0.,0.,1.));
#718=VECTOR('',#717,1.);
#719=CARTESIAN_POINT('',(69.85,38.1,-12.7));
#720=LINE('',#719,#718);
#721=CARTESIAN_POINT('',(69.85,38.1,-3.175));
#722=VERTEX_POINT('',#721);
#723=EDGE_CURVE('E460',#714,#722,#720,.T.);
#724=ORIENTED_EDGE('',*,*,#723,.T.);
#725=DIRECTION('',(0.,1.,0.));
#726=VECTOR('',#725,1.);
#727=CARTESIAN_POINT('',(69.85,12.7,-3.175));
#728=LINE('',#727,#726);
#729=EDGE_CURVE('E244',#722,#704,#728,.F.);
#730=ORIENTED_EDGE('',*,*,#729,.T.);
#731=EDGE_LOOP('',(#708,#716,#724,#730));
#732=FACE_BOUND('',#731,.T.);
#733=ADVANCED_FACE('F764',(#732),#698,.T.);
#734=CARTESIAN_POINT('',(50.8,38.1,-12.7));
#735=DIRECTION('',(0.,0.,-1.));
#736=DIRECTION('',(-1.,0.,0.));
#737=AXIS2_PLACEMENT_3D('',#734,#735,#736);
#738=PLANE('',#737);
#739=DIRECTION('',(1.,0.,0.));
#740=VECTOR('',#739,1.);
#741=CARTESIAN_POINT('',(50.8,15.875,-12.7));
#742=LINE('',#741,#740);
#743=CARTESIAN_POINT('',(66.675,15.875,-12.7));
#744=VERTEX_POINT('',#743);
#745=CARTESIAN_POINT('',(34.925,15.875,-12.7));
#746=VERTEX_POINT('',#745);
#747=EDGE_CURVE('E554',#744,#746,#742,.F.);
#748=ORIENTED_EDGE('',*,*,#747,.T.);
#749=DIRECTION('',(0.,-1.,0.));
#750=VECTOR('',#749,1.);
#751=CARTESIAN_POINT('',(34.925,38.1,-12.7));
#752=LINE('',#751,#750);
#753=CARTESIAN_POINT('',(34.925,38.1,-12.7));
#754=VERTEX_POINT('',#753);
#755=EDGE_CURVE('E560',#746,#754,#752,.F.);
#756=ORIENTED_EDGE('',*,*,#755,.T.);
#757=CARTESIAN_POINT('',(50.8,38.1,-12.7));
#758=DIRECTION('',(0.,0.,-1.));
#759=DIRECTION('',(-1.,0.,0.));
#760=AXIS2_PLACEMENT_3D('',#757,#758,#759);
#761=CIRCLE('',#760,15.875);
#762=CARTESIAN_POINT('',(66.675,38.1,-12.7));
#763=VERTEX_POINT('',#762);
#764=EDGE_CURVE('E551',#754,#763,#761,.T.);
#765=ORIENTED_EDGE('',*,*,#764,.T.);
#766=DIRECTION('',(0.,1.,0.));
#767=VECTOR('',#766,1.);
#768=CARTESIAN_POINT('',(66.675,38.1,-12.7));
#769=LINE('',#768,#767);
#770=EDGE_CURVE('E553',#763,#744,#769,.F.);
#771=ORIENTED_EDGE('',*,*,#770,.T.);
#772=EDGE_LOOP('',(#748,#756,#765,#771));
#773=FACE_BOUND('',#772,.T.);
#774=CARTESIAN_POINT('',(50.8,38.1,-12.7));
#775=DIRECTION('',(0.,0.,-1.));
#776=DIRECTION('',(-1.,0.,0.));
#777=AXIS2_PLACEMENT_3D('',#774,#775,#776);
#778=CIRCLE('',#777,3.37819999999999);
#779=CARTESIAN_POINT('',(47.4218,38.1,-12.7));
#780=VERTEX_POINT('',#779);
#781=EDGE_CURVE('E455',#780,#780,#778,.T.);
#782=ORIENTED_EDGE('',*,*,#781,.F.);
#783=EDGE_LOOP('',(#782));
#784=FACE_BOUND('',#783,.T.);
#785=ADVANCED_FACE('F779',(#773,#784),#738,.T.);
#786=CARTESIAN_POINT('',(50.8,38.1,-12.7));
#787=DIRECTION('',(0.,0.,1.));
#788=DIRECTION('',(1.,0.,0.));
#789=AXIS2_PLACEMENT_3D('',#786,#787,#788);
#790=CYLINDRICAL_SURFACE('',#789,19.05);
#791=ORIENTED_EDGE('',*,*,#723,.F.);
#792=CARTESIAN_POINT('',(50.8,38.1,-9.525));
#793=DIRECTION('',(0.,0.,-1.));
#794=DIRECTION('',(-1.,0.,0.));
#795=AXIS2_PLACEMENT_3D('',#792,#793,#794);
#796=CIRCLE('',#795,19.05);
#797=EDGE_CURVE('E581',#714,#664,#796,.F.);
#798=ORIENTED_EDGE('',*,*,#797,.T.);
#799=ORIENTED_EDGE('',*,*,#667,.T.);
#800=CARTESIAN_POINT('',(50.8,38.1,-3.175));
#801=DIRECTION('',(0.,0.,-1.));
#802=DIRECTION('',(-1.,0.,0.));
#803=AXIS2_PLACEMENT_3D('',#800,#801,#802);
#804=CIRCLE('',#803,19.05);
#805=EDGE_CURVE('E578',#666,#722,#804,.T.);
#806=ORIENTED_EDGE('',*,*,#805,.T.);
#807=EDGE_LOOP('',(#791,#798,#799,#806));
#808=FACE_BOUND('',#807,.T.);
#809=ADVANCED_FACE('F776',(#808),#790,.T.);
#810=CARTESIAN_POINT('',(50.8,38.1,-1.13686837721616E-10));
#811=DIRECTION('',(0.,0.,1.));
#812=DIRECTION('',(1.,0.,0.));
#813=AXIS2_PLACEMENT_3D('',#810,#811,#812);
#814=CYLINDRICAL_SURFACE('',#813,9.52499999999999);
#815=CARTESIAN_POINT('',(50.8,38.1,-4.77520000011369));
#816=DIRECTION('',(0.,0.,1.));
#817=DIRECTION('',(1.,0.,0.));
#818=AXIS2_PLACEMENT_3D('',#815,#816,#817);
#819=CIRCLE('',#818,9.52499999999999);
#820=CARTESIAN_POINT('',(60.325,38.1,-4.77520000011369));
#821=VERTEX_POINT('',#820);
#822=EDGE_CURVE('E450',#821,#821,#819,.T.);
#823=ORIENTED_EDGE('',*,*,#822,.F.);
#824=EDGE_LOOP('',(#823));
#825=FACE_BOUND('',#824,.T.);
#826=ORIENTED_EDGE('',*,*,#257,.T.);
#827=EDGE_LOOP('',(#826));
#828=FACE_BOUND('',#827,.T.);
#829=ADVANCED_FACE('F780',(#825,#828),#814,.F.);
#830=CARTESIAN_POINT('',(54.1782,38.1,-4.77520000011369));
#831=DIRECTION('',(0.,0.,-1.));
#832=DIRECTION('',(-1.,0.,0.));
#833=AXIS2_PLACEMENT_3D('',#830,#831,#832);
#834=PLANE('',#833);
#835=CARTESIAN_POINT('',(50.8,38.1,-4.77520000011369));
#836=DIRECTION('',(0.,0.,1.));
#837=DIRECTION('',(1.,0.,0.));
#838=AXIS2_PLACEMENT_3D('',#835,#836,#837);
#839=CIRCLE('',#838,3.3782);
#840=CARTESIAN_POINT('',(54.1782,38.1,-4.77520000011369));
#841=VERTEX_POINT('',#840);
#842=EDGE_CURVE('E437',#841,#841,#839,.T.);
#843=ORIENTED_EDGE('',*,*,#842,.F.);
#844=EDGE_LOOP('',(#843));
#845=FACE_BOUND('',#844,.T.);
#846=ORIENTED_EDGE('',*,*,#822,.T.);
#847=EDGE_LOOP('',(#846));
#848=FACE_BOUND('',#847,.T.);
#849=ADVANCED_FACE('F787',(#845,#848),#834,.F.);
#850=CARTESIAN_POINT('',(50.8,38.1,-1.13686837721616E-10));
#851=DIRECTION('',(0.,0.,1.));
#852=DIRECTION('',(1.,0.,0.));
#853=AXIS2_PLACEMENT_3D('',#850,#851,#852);
#854=CYLINDRICAL_SURFACE('',#853,3.37819999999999);
#855=ORIENTED_EDGE('',*,*,#781,.T.);
#856=EDGE_LOOP('',(#855));
#857=FACE_BOUND('',#856,.T.);
#858=ORIENTED_EDGE('',*,*,#842,.T.);
#859=EDGE_LOOP('',(#858));
#860=FACE_BOUND('',#859,.T.);
#861=ADVANCED_FACE('F786',(#857,#860),#854,.F.);
#862=CARTESIAN_POINT('',(31.75,3.17499999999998,-38.1));
#863=DIRECTION('',(0.,1.,0.));
#864=DIRECTION('',(0.,0.,1.));
#865=AXIS2_PLACEMENT_3D('',#862,#863,#864);
#866=PLANE('',#865);
#867=ORIENTED_EDGE('',*,*,#456,.F.);
#868=DIRECTION('',(0.,0.,-1.));
#869=VECTOR('',#868,1.);
#870=CARTESIAN_POINT('',(64.3507386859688,3.17499999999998,-38.1));
#871=LINE('',#870,#869);
#872=EDGE_CURVE('E474',#447,#351,#871,.F.);
#873=ORIENTED_EDGE('',*,*,#872,.T.);
#874=ORIENTED_EDGE('',*,*,#352,.T.);
#875=DIRECTION('',(0.,0.,1.));
#876=VECTOR('',#875,1.);
#877=CARTESIAN_POINT('',(37.2492613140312,3.17499999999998,-38.1));
#878=LINE('',#877,#876);
#879=EDGE_CURVE('E470',#343,#455,#878,.F.);
#880=ORIENTED_EDGE('',*,*,#879,.T.);
#881=EDGE_LOOP('',(#867,#873,#874,#880));
#882=FACE_BOUND('',#881,.T.);
#883=ADVANCED_FACE('F677',(#882),#866,.F.);
#884=CARTESIAN_POINT('',(12.7,12.6999999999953,-25.4));
#885=DIRECTION('',(0.,1.,0.));
#886=DIRECTION('',(0.,0.,1.));
#887=AXIS2_PLACEMENT_3D('',#884,#885,#886);
#888=CYLINDRICAL_SURFACE('',#887,3.57187499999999);
#889=ORIENTED_EDGE('',*,*,#157,.F.);
#890=EDGE_LOOP('',(#889));
#891=FACE_BOUND('',#890,.T.);
#892=ORIENTED_EDGE('',*,*,#612,.T.);
#893=EDGE_LOOP('',(#892));
#894=FACE_BOUND('',#893,.T.);
#895=ADVANCED_FACE('F748',(#891,#894),#888,.F.);
#896=CARTESIAN_POINT('',(88.9,12.6999999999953,-25.4));
#897=DIRECTION('',(0.,1.,0.));
#898=DIRECTION('',(0.,0.,1.));
#899=AXIS2_PLACEMENT_3D('',#896,#897,#898);
#900=CYLINDRICAL_SURFACE('',#899,3.571875);
#901=ORIENTED_EDGE('',*,*,#624,.F.);
#902=EDGE_LOOP('',(#901));
#903=FACE_BOUND('',#902,.T.);
#904=ORIENTED_EDGE('',*,*,#601,.T.);
#905=EDGE_LOOP('',(#904));
#906=FACE_BOUND('',#905,.T.);
#907=ADVANCED_FACE('F736',(#903,#906),#900,.F.);
#908=CARTESIAN_POINT('',(64.3507386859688,-3.17500000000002,-38.1));
#909=DIRECTION('',(0.,0.,-1.));
#910=DIRECTION('',(-1.,0.,0.));
#911=AXIS2_PLACEMENT_3D('',#908,#909,#910);
#912=CYLINDRICAL_SURFACE('',#911,6.35);
#913=ORIENTED_EDGE('',*,*,#448,.F.);
#914=ORIENTED_EDGE('',*,*,#641,.T.);
#915=ORIENTED_EDGE('',*,*,#361,.F.);
#916=ORIENTED_EDGE('',*,*,#872,.F.);
#917=EDGE_LOOP('',(#913,#914,#915,#916));
#918=FACE_BOUND('',#917,.T.);
#919=ADVANCED_FACE('F738',(#918),#912,.F.);
#920=CARTESIAN_POINT('',(37.2492613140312,-3.17500000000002,-38.1));
#921=DIRECTION('',(0.,0.,1.));
#922=DIRECTION('',(1.,0.,0.));
#923=AXIS2_PLACEMENT_3D('',#920,#921,#922);
#924=CYLINDRICAL_SURFACE('',#923,6.35);
#925=ORIENTED_EDGE('',*,*,#463,.F.);
#926=ORIENTED_EDGE('',*,*,#879,.F.);
#927=ORIENTED_EDGE('',*,*,#344,.F.);
#928=ORIENTED_EDGE('',*,*,#209,.F.);
#929=EDGE_LOOP('',(#925,#926,#927,#928));
#930=FACE_BOUND('',#929,.T.);
#931=ADVANCED_FACE('F432',(#930),#924,.F.);
#932=CARTESIAN_POINT('',(6.35,12.7,-6.35));
#933=DIRECTION('',(0.,-1.,0.));
#934=DIRECTION('',(0.,0.,-1.));
#935=AXIS2_PLACEMENT_3D('',#932,#933,#934);
#936=CYLINDRICAL_SURFACE('',#935,6.35);
#937=ORIENTED_EDGE('',*,*,#334,.F.);
#938=CARTESIAN_POINT('',(6.35,9.525,-6.35));
#939=DIRECTION('',(0.,-1.,0.));
#940=DIRECTION('',(0.,0.,-1.));
#941=AXIS2_PLACEMENT_3D('',#938,#939,#940);
#942=CIRCLE('',#941,6.35);
#943=EDGE_CURVE('E583',#327,#224,#942,.T.);
#944=ORIENTED_EDGE('',*,*,#943,.T.);
#945=ORIENTED_EDGE('',*,*,#225,.F.);
#946=ORIENTED_EDGE('',*,*,#178,.F.);
#947=EDGE_LOOP('',(#937,#944,#945,#946));
#948=FACE_BOUND('',#947,.T.);
#949=ADVANCED_FACE('F691',(#948),#936,.T.);
#950=CARTESIAN_POINT('',(95.25,12.7,-6.35));
#951=DIRECTION('',(0.,-1.,0.));
#952=DIRECTION('',(0.,0.,-1.));
#953=AXIS2_PLACEMENT_3D('',#950,#951,#952);
#954=CYLINDRICAL_SURFACE('',#953,6.35);
#955=ORIENTED_EDGE('',*,*,#397,.F.);
#956=CARTESIAN_POINT('',(95.25,9.525,-6.35));
#957=DIRECTION('',(0.,-1.,0.));
#958=DIRECTION('',(0.,0.,-1.));
#959=AXIS2_PLACEMENT_3D('',#956,#957,#958);
#960=CIRCLE('',#959,6.35);
#961=EDGE_CURVE('E557',#388,#268,#960,.T.);
#962=ORIENTED_EDGE('',*,*,#961,.T.);
#963=ORIENTED_EDGE('',*,*,#269,.F.);
#964=ORIENTED_EDGE('',*,*,#634,.F.);
#965=EDGE_LOOP('',(#955,#962,#963,#964));
#966=FACE_BOUND('',#965,.T.);
#967=ADVANCED_FACE('F920',(#966),#954,.T.);
#968=CARTESIAN_POINT('',(95.25,12.7,-31.75));
#969=DIRECTION('',(0.,-1.,0.));
#970=DIRECTION('',(0.,0.,-1.));
#971=AXIS2_PLACEMENT_3D('',#968,#969,#970);
#972=CYLINDRICAL_SURFACE('',#971,6.35);
#973=ORIENTED_EDGE('',*,*,#435,.F.);
#974=CARTESIAN_POINT('',(95.25,9.525,-31.75));
#975=DIRECTION('',(0.,-1.,0.));
#976=DIRECTION('',(0.,0.,-1.));
#977=AXIS2_PLACEMENT_3D('',#974,#975,#976);
#978=CIRCLE('',#977,6.35);
#979=EDGE_CURVE('E533',#426,#380,#978,.T.);
#980=ORIENTED_EDGE('',*,*,#979,.T.);
#981=ORIENTED_EDGE('',*,*,#381,.F.);
#982=ORIENTED_EDGE('',*,*,#649,.F.);
#983=EDGE_LOOP('',(#973,#980,#981,#982));
#984=FACE_BOUND('',#983,.T.);
#985=ADVANCED_FACE('F723',(#984),#972,.T.);
#986=CARTESIAN_POINT('',(6.35,12.7,-31.75));
#987=DIRECTION('',(0.,-1.,0.));
#988=DIRECTION('',(0.,0.,-1.));
#989=AXIS2_PLACEMENT_3D('',#986,#987,#988);
#990=CYLINDRICAL_SURFACE('',#989,6.35);
#991=ORIENTED_EDGE('',*,*,#239,.F.);
#992=CARTESIAN_POINT('',(6.35,9.525,-31.75));
#993=DIRECTION('',(0.,-1.,0.));
#994=DIRECTION('',(0.,0.,-1.));
#995=AXIS2_PLACEMENT_3D('',#992,#993,#994);
#996=CIRCLE('',#995,6.35);
#997=EDGE_CURVE('E548',#232,#418,#996,.T.);
#998=ORIENTED_EDGE('',*,*,#997,.T.);
#999=ORIENTED_EDGE('',*,*,#419,.F.);
#1000=ORIENTED_EDGE('',*,*,#195,.F.);
#1001=EDGE_LOOP('',(#991,#998,#999,#1000));
#1002=FACE_BOUND('',#1001,.T.);
#1003=ADVANCED_FACE('F703',(#1002),#990,.T.);
#1004=CARTESIAN_POINT('',(34.925,0.,-9.525));
#1005=DIRECTION('',(0.,-1.,0.));
#1006=DIRECTION('',(0.,0.,-1.));
#1007=AXIS2_PLACEMENT_3D('',#1004,#1005,#1006);
#1008=CYLINDRICAL_SURFACE('',#1007,3.175);
#1009=CARTESIAN_POINT('',(34.925,15.875,-9.525));
#1010=DIRECTION('',(0.,-1.,0.));
#1011=DIRECTION('',(0.,0.,-1.));
#1012=AXIS2_PLACEMENT_3D('',#1009,#1010,#1011);
#1013=CIRCLE('',#1012,3.175);
#1014=EDGE_CURVE('E647',#674,#746,#1013,.T.);
#1015=ORIENTED_EDGE('',*,*,#1014,.F.);
#1016=ORIENTED_EDGE('',*,*,#675,.F.);
#1017=CARTESIAN_POINT('',(34.925,38.1,-9.525));
#1018=DIRECTION('',(0.,1.,0.));
#1019=DIRECTION('',(0.,0.,1.));
#1020=AXIS2_PLACEMENT_3D('',#1017,#1018,#1019);
#1021=CIRCLE('',#1020,3.175);
#1022=EDGE_CURVE('E230',#754,#664,#1021,.T.);
#1023=ORIENTED_EDGE('',*,*,#1022,.F.);
#1024=ORIENTED_EDGE('',*,*,#755,.F.);
#1025=EDGE_LOOP('',(#1015,#1016,#1023,#1024));
#1026=FACE_BOUND('',#1025,.T.);
#1027=ADVANCED_FACE('F227',(#1026),#1008,.T.);
#1028=CARTESIAN_POINT('',(50.8,38.1,-9.525));
#1029=DIRECTION('',(0.,0.,-1.));
#1030=DIRECTION('',(-1.,0.,0.));
#1031=AXIS2_PLACEMENT_3D('',#1028,#1029,#1030);
#1032=TOROIDAL_SURFACE('',#1031,15.875,3.175);
#1033=ORIENTED_EDGE('',*,*,#1022,.T.);
#1034=ORIENTED_EDGE('',*,*,#797,.F.);
#1035=CARTESIAN_POINT('',(66.675,38.1,-9.525));
#1036=DIRECTION('',(0.,-1.,0.));
#1037=DIRECTION('',(0.,0.,-1.));
#1038=AXIS2_PLACEMENT_3D('',#1035,#1036,#1037);
#1039=CIRCLE('',#1038,3.175);
#1040=EDGE_CURVE('E650',#763,#714,#1039,.T.);
#1041=ORIENTED_EDGE('',*,*,#1040,.F.);
#1042=ORIENTED_EDGE('',*,*,#764,.F.);
#1043=EDGE_LOOP('',(#1033,#1034,#1041,#1042));
#1044=FACE_BOUND('',#1043,.T.);
#1045=ADVANCED_FACE('F954',(#1044),#1032,.T.);
#1046=CARTESIAN_POINT('',(34.925,15.875,-9.525));
#1047=DIRECTION('',(0.,-1.,0.));
#1048=DIRECTION('',(0.,0.,-1.));
#1049=AXIS2_PLACEMENT_3D('',#1046,#1047,#1048);
#1050=TOROIDAL_SURFACE('',#1049,6.35,3.175);
#1051=CARTESIAN_POINT('',(28.575,15.875,-9.525));
#1052=DIRECTION('',(0.,0.,1.));
#1053=DIRECTION('',(1.,0.,0.));
#1054=AXIS2_PLACEMENT_3D('',#1051,#1052,#1053);
#1055=CIRCLE('',#1054,3.175);
#1056=EDGE_CURVE('E645',#674,#574,#1055,.F.);
#1057=ORIENTED_EDGE('',*,*,#1056,.F.);
#1058=ORIENTED_EDGE('',*,*,#1014,.T.);
#1059=CARTESIAN_POINT('',(34.925,15.875,-15.875));
#1060=DIRECTION('',(1.,0.,0.));
#1061=DIRECTION('',(0.,0.,-1.));
#1062=AXIS2_PLACEMENT_3D('',#1059,#1060,#1061);
#1063=CIRCLE('',#1062,3.175);
#1064=EDGE_CURVE('E643',#583,#746,#1063,.F.);
#1065=ORIENTED_EDGE('',*,*,#1064,.F.);
#1066=ORIENTED_EDGE('',*,*,#584,.T.);
#1067=EDGE_LOOP('',(#1057,#1058,#1065,#1066));
#1068=FACE_BOUND('',#1067,.T.);
#1069=ADVANCED_FACE('F964',(#1068),#1050,.F.);
#1070=CARTESIAN_POINT('',(66.675,38.1,-9.525));
#1071=DIRECTION('',(0.,1.,0.));
#1072=DIRECTION('',(0.,0.,1.));
#1073=AXIS2_PLACEMENT_3D('',#1070,#1071,#1072);
#1074=CYLINDRICAL_SURFACE('',#1073,3.175);
#1075=ORIENTED_EDGE('',*,*,#1040,.T.);
#1076=ORIENTED_EDGE('',*,*,#715,.F.);
#1077=CARTESIAN_POINT('',(66.675,15.875,-9.525));
#1078=DIRECTION('',(0.,-1.,0.));
#1079=DIRECTION('',(0.,0.,-1.));
#1080=AXIS2_PLACEMENT_3D('',#1077,#1078,#1079);
#1081=CIRCLE('',#1080,3.175);
#1082=EDGE_CURVE('E636',#744,#706,#1081,.T.);
#1083=ORIENTED_EDGE('',*,*,#1082,.F.);
#1084=ORIENTED_EDGE('',*,*,#770,.F.);
#1085=EDGE_LOOP('',(#1075,#1076,#1083,#1084));
#1086=FACE_BOUND('',#1085,.T.);
#1087=ADVANCED_FACE('F972',(#1086),#1074,.T.);
#1088=CARTESIAN_POINT('',(0.,15.875,-15.875));
#1089=DIRECTION('',(1.,0.,0.));
#1090=DIRECTION('',(0.,0.,-1.));
#1091=AXIS2_PLACEMENT_3D('',#1088,#1089,#1090);
#1092=CYLINDRICAL_SURFACE('',#1091,3.175);
#1093=ORIENTED_EDGE('',*,*,#1064,.T.);
#1094=ORIENTED_EDGE('',*,*,#747,.F.);
#1095=CARTESIAN_POINT('',(66.675,15.875,-15.875));
#1096=DIRECTION('',(-1.,0.,0.));
#1097=DIRECTION('',(0.,0.,1.));
#1098=AXIS2_PLACEMENT_3D('',#1095,#1096,#1097);
#1099=CIRCLE('',#1098,3.175);
#1100=EDGE_CURVE('E633',#482,#744,#1099,.T.);
#1101=ORIENTED_EDGE('',*,*,#1100,.F.);
#1102=ORIENTED_EDGE('',*,*,#590,.F.);
#1103=EDGE_LOOP('',(#1093,#1094,#1101,#1102));
#1104=FACE_BOUND('',#1103,.T.);
#1105=ADVANCED_FACE('F981',(#1104),#1092,.F.);
#1106=CARTESIAN_POINT('',(28.575,15.875,-38.1));
#1107=DIRECTION('',(0.,0.,-1.));
#1108=DIRECTION('',(-1.,0.,0.));
#1109=AXIS2_PLACEMENT_3D('',#1106,#1107,#1108);
#1110=CYLINDRICAL_SURFACE('',#1109,3.175);
#1111=ORIENTED_EDGE('',*,*,#1056,.T.);
#1112=ORIENTED_EDGE('',*,*,#575,.F.);
#1113=CARTESIAN_POINT('',(28.575,15.875,-3.175));
#1114=DIRECTION('',(0.,0.,-1.));
#1115=DIRECTION('',(-1.,0.,0.));
#1116=AXIS2_PLACEMENT_3D('',#1113,#1114,#1115);
#1117=CIRCLE('',#1116,3.175);
#1118=EDGE_CURVE('E629',#682,#566,#1117,.T.);
#1119=ORIENTED_EDGE('',*,*,#1118,.F.);
#1120=ORIENTED_EDGE('',*,*,#683,.F.);
#1121=EDGE_LOOP('',(#1111,#1112,#1119,#1120));
#1122=FACE_BOUND('',#1121,.T.);
#1123=ADVANCED_FACE('F1000',(#1122),#1110,.F.);
#1124=CARTESIAN_POINT('',(34.925,12.7,-3.175));
#1125=DIRECTION('',(0.,1.,0.));
#1126=DIRECTION('',(0.,0.,1.));
#1127=AXIS2_PLACEMENT_3D('',#1124,#1125,#1126);
#1128=CYLINDRICAL_SURFACE('',#1127,3.175);
#1129=CARTESIAN_POINT('',(34.925,15.875,-3.175));
#1130=DIRECTION('',(0.,-1.,0.));
#1131=DIRECTION('',(0.,0.,-1.));
#1132=AXIS2_PLACEMENT_3D('',#1129,#1130,#1131);
#1133=CIRCLE('',#1132,3.175);
#1134=EDGE_CURVE('E628',#310,#682,#1133,.T.);
#1135=ORIENTED_EDGE('',*,*,#1134,.F.);
#1136=ORIENTED_EDGE('',*,*,#311,.F.);
#1137=CARTESIAN_POINT('',(34.925,38.1,-3.175));
#1138=DIRECTION('',(0.,1.,0.));
#1139=DIRECTION('',(0.,0.,1.));
#1140=AXIS2_PLACEMENT_3D('',#1137,#1138,#1139);
#1141=CIRCLE('',#1140,3.175);
#1142=EDGE_CURVE('E638',#666,#302,#1141,.T.);
#1143=ORIENTED_EDGE('',*,*,#1142,.F.);
#1144=ORIENTED_EDGE('',*,*,#689,.F.);
#1145=EDGE_LOOP('',(#1135,#1136,#1143,#1144));
#1146=FACE_BOUND('',#1145,.T.);
#1147=ADVANCED_FACE('F1006',(#1146),#1128,.T.);
#1148=CARTESIAN_POINT('',(50.8,38.1,-3.175));
#1149=DIRECTION('',(0.,0.,-1.));
#1150=DIRECTION('',(-1.,0.,0.));
#1151=AXIS2_PLACEMENT_3D('',#1148,#1149,#1150);
#1152=TOROIDAL_SURFACE('',#1151,15.875,3.175);
#1153=ORIENTED_EDGE('',*,*,#1142,.T.);
#1154=ORIENTED_EDGE('',*,*,#303,.F.);
#1155=CARTESIAN_POINT('',(66.675,38.1,-3.175));
#1156=DIRECTION('',(0.,-1.,0.));
#1157=DIRECTION('',(0.,0.,-1.));
#1158=AXIS2_PLACEMENT_3D('',#1155,#1156,#1157);
#1159=CIRCLE('',#1158,3.175);
#1160=EDGE_CURVE('E622',#722,#293,#1159,.T.);
#1161=ORIENTED_EDGE('',*,*,#1160,.F.);
#1162=ORIENTED_EDGE('',*,*,#805,.F.);
#1163=EDGE_LOOP('',(#1153,#1154,#1161,#1162));
#1164=FACE_BOUND('',#1163,.T.);
#1165=ADVANCED_FACE('F1019',(#1164),#1152,.T.);
#1166=CARTESIAN_POINT('',(66.675,15.875,-9.525));
#1167=DIRECTION('',(0.,-1.,0.));
#1168=DIRECTION('',(0.,0.,-1.));
#1169=AXIS2_PLACEMENT_3D('',#1166,#1167,#1168);
#1170=TOROIDAL_SURFACE('',#1169,6.35,3.175);
#1171=ORIENTED_EDGE('',*,*,#1100,.T.);
#1172=ORIENTED_EDGE('',*,*,#1082,.T.);
#1173=CARTESIAN_POINT('',(73.025,15.875,-9.525));
#1174=DIRECTION('',(0.,0.,1.));
#1175=DIRECTION('',(1.,0.,0.));
#1176=AXIS2_PLACEMENT_3D('',#1173,#1174,#1175);
#1177=CIRCLE('',#1176,3.175);
#1178=EDGE_CURVE('E625',#480,#706,#1177,.F.);
#1179=ORIENTED_EDGE('',*,*,#1178,.F.);
#1180=ORIENTED_EDGE('',*,*,#483,.T.);
#1181=EDGE_LOOP('',(#1171,#1172,#1179,#1180));
#1182=FACE_BOUND('',#1181,.T.);
#1183=ADVANCED_FACE('F1032',(#1182),#1170,.F.);
#1184=CARTESIAN_POINT('',(28.575,15.875,-3.175));
#1185=DIRECTION('',(0.,0.,-1.));
#1186=DIRECTION('',(-1.,0.,0.));
#1187=AXIS2_PLACEMENT_3D('',#1184,#1185,#1186);
#1188=TOROIDAL_SURFACE('',#1187,6.35,3.175);
#1189=ORIENTED_EDGE('',*,*,#1134,.T.);
#1190=ORIENTED_EDGE('',*,*,#1118,.T.);
#1191=CARTESIAN_POINT('',(28.575,9.525,-3.175));
#1192=DIRECTION('',(1.,0.,0.));
#1193=DIRECTION('',(0.,0.,-1.));
#1194=AXIS2_PLACEMENT_3D('',#1191,#1192,#1193);
#1195=CIRCLE('',#1194,3.175);
#1196=EDGE_CURVE('E620',#319,#566,#1195,.F.);
#1197=ORIENTED_EDGE('',*,*,#1196,.F.);
#1198=ORIENTED_EDGE('',*,*,#320,.T.);
#1199=EDGE_LOOP('',(#1189,#1190,#1197,#1198));
#1200=FACE_BOUND('',#1199,.T.);
#1201=ADVANCED_FACE('F1045',(#1200),#1188,.T.);
#1202=CARTESIAN_POINT('',(66.675,12.7,-3.175));
#1203=DIRECTION('',(0.,-1.,0.));
#1204=DIRECTION('',(0.,0.,-1.));
#1205=AXIS2_PLACEMENT_3D('',#1202,#1203,#1204);
#1206=CYLINDRICAL_SURFACE('',#1205,3.175);
#1207=ORIENTED_EDGE('',*,*,#1160,.T.);
#1208=ORIENTED_EDGE('',*,*,#294,.F.);
#1209=CARTESIAN_POINT('',(66.675,15.875,-3.175));
#1210=DIRECTION('',(0.,-1.,0.));
#1211=DIRECTION('',(0.,0.,-1.));
#1212=AXIS2_PLACEMENT_3D('',#1209,#1210,#1211);
#1213=CIRCLE('',#1212,3.175);
#1214=EDGE_CURVE('E618',#704,#285,#1213,.T.);
#1215=ORIENTED_EDGE('',*,*,#1214,.F.);
#1216=ORIENTED_EDGE('',*,*,#729,.F.);
#1217=EDGE_LOOP('',(#1207,#1208,#1215,#1216));
#1218=FACE_BOUND('',#1217,.T.);
#1219=ADVANCED_FACE('F1054',(#1218),#1206,.T.);
#1220=CARTESIAN_POINT('',(73.025,15.875,-38.1));
#1221=DIRECTION('',(0.,0.,1.));
#1222=DIRECTION('',(1.,0.,0.));
#1223=AXIS2_PLACEMENT_3D('',#1220,#1221,#1222);
#1224=CYLINDRICAL_SURFACE('',#1223,3.175);
#1225=ORIENTED_EDGE('',*,*,#1178,.T.);
#1226=ORIENTED_EDGE('',*,*,#707,.F.);
#1227=CARTESIAN_POINT('',(73.025,15.875,-3.175));
#1228=DIRECTION('',(0.,0.,-1.));
#1229=DIRECTION('',(-1.,0.,0.));
#1230=AXIS2_PLACEMENT_3D('',#1227,#1228,#1229);
#1231=CIRCLE('',#1230,3.175);
#1232=EDGE_CURVE('E614',#490,#704,#1231,.T.);
#1233=ORIENTED_EDGE('',*,*,#1232,.F.);
#1234=ORIENTED_EDGE('',*,*,#491,.F.);
#1235=EDGE_LOOP('',(#1225,#1226,#1233,#1234));
#1236=FACE_BOUND('',#1235,.T.);
#1237=ADVANCED_FACE('F1062',(#1236),#1224,.F.);
#1238=CARTESIAN_POINT('',(0.,9.525,-3.175));
#1239=DIRECTION('',(1.,0.,0.));
#1240=DIRECTION('',(0.,0.,-1.));
#1241=AXIS2_PLACEMENT_3D('',#1238,#1239,#1240);
#1242=CYLINDRICAL_SURFACE('',#1241,3.175);
#1243=ORIENTED_EDGE('',*,*,#1196,.T.);
#1244=ORIENTED_EDGE('',*,*,#567,.F.);
#1245=CARTESIAN_POINT('',(6.35,9.525,-3.175));
#1246=DIRECTION('',(-1.,0.,0.));
#1247=DIRECTION('',(0.,0.,1.));
#1248=AXIS2_PLACEMENT_3D('',#1245,#1246,#1247);
#1249=CIRCLE('',#1248,3.175);
#1250=EDGE_CURVE('E607',#327,#558,#1249,.T.);
#1251=ORIENTED_EDGE('',*,*,#1250,.F.);
#1252=ORIENTED_EDGE('',*,*,#328,.F.);
#1253=EDGE_LOOP('',(#1243,#1244,#1251,#1252));
#1254=FACE_BOUND('',#1253,.T.);
#1255=ADVANCED_FACE('F1080',(#1254),#1242,.T.);
#1256=CARTESIAN_POINT('',(73.025,15.875,-3.175));
#1257=DIRECTION('',(0.,0.,-1.));
#1258=DIRECTION('',(-1.,0.,0.));
#1259=AXIS2_PLACEMENT_3D('',#1256,#1257,#1258);
#1260=TOROIDAL_SURFACE('',#1259,6.35,3.175);
#1261=ORIENTED_EDGE('',*,*,#1214,.T.);
#1262=ORIENTED_EDGE('',*,*,#286,.T.);
#1263=CARTESIAN_POINT('',(73.025,9.525,-3.175));
#1264=DIRECTION('',(-1.,0.,0.));
#1265=DIRECTION('',(0.,0.,1.));
#1266=AXIS2_PLACEMENT_3D('',#1263,#1264,#1265);
#1267=CIRCLE('',#1266,3.175);
#1268=EDGE_CURVE('E610',#490,#276,#1267,.F.);
#1269=ORIENTED_EDGE('',*,*,#1268,.F.);
#1270=ORIENTED_EDGE('',*,*,#1232,.T.);
#1271=EDGE_LOOP('',(#1261,#1262,#1269,#1270));
#1272=FACE_BOUND('',#1271,.T.);
#1273=ADVANCED_FACE('F1088',(#1272),#1260,.T.);
#1274=CARTESIAN_POINT('',(6.35,9.525,-6.35));
#1275=DIRECTION('',(0.,-1.,0.));
#1276=DIRECTION('',(0.,0.,-1.));
#1277=AXIS2_PLACEMENT_3D('',#1274,#1275,#1276);
#1278=DEGENERATE_TOROIDAL_SURFACE('',#1277,3.175,3.175,.T.);
#1279=ORIENTED_EDGE('',*,*,#1250,.T.);
#1280=ORIENTED_EDGE('',*,*,#559,.F.);
#1281=CARTESIAN_POINT('',(3.175,9.525,-6.35));
#1282=DIRECTION('',(0.,0.,-1.));
#1283=DIRECTION('',(-1.,0.,0.));
#1284=AXIS2_PLACEMENT_3D('',#1281,#1282,#1283);
#1285=CIRCLE('',#1284,3.175);
#1286=EDGE_CURVE('E603',#224,#549,#1285,.T.);
#1287=ORIENTED_EDGE('',*,*,#1286,.F.);
#1288=ORIENTED_EDGE('',*,*,#943,.F.);
#1289=EDGE_LOOP('',(#1279,#1280,#1287,#1288));
#1290=FACE_BOUND('',#1289,.T.);
#1291=ADVANCED_FACE('F694',(#1290),#1278,.T.);
#1292=CARTESIAN_POINT('',(0.,9.525,-3.175));
#1293=DIRECTION('',(1.,0.,0.));
#1294=DIRECTION('',(0.,0.,-1.));
#1295=AXIS2_PLACEMENT_3D('',#1292,#1293,#1294);
#1296=CYLINDRICAL_SURFACE('',#1295,3.175);
#1297=ORIENTED_EDGE('',*,*,#1268,.T.);
#1298=ORIENTED_EDGE('',*,*,#277,.F.);
#1299=CARTESIAN_POINT('',(95.25,9.525,-3.175));
#1300=DIRECTION('',(1.,0.,0.));
#1301=DIRECTION('',(0.,0.,-1.));
#1302=AXIS2_PLACEMENT_3D('',#1299,#1300,#1301);
#1303=CIRCLE('',#1302,3.175);
#1304=EDGE_CURVE('E604',#498,#268,#1303,.T.);
#1305=ORIENTED_EDGE('',*,*,#1304,.F.);
#1306=ORIENTED_EDGE('',*,*,#499,.F.);
#1307=EDGE_LOOP('',(#1297,#1298,#1305,#1306));
#1308=FACE_BOUND('',#1307,.T.);
#1309=ADVANCED_FACE('F1108',(#1308),#1296,.T.);
#1310=CARTESIAN_POINT('',(3.175,9.525,-38.1));
#1311=DIRECTION('',(0.,0.,1.));
#1312=DIRECTION('',(1.,0.,0.));
#1313=AXIS2_PLACEMENT_3D('',#1310,#1311,#1312);
#1314=CYLINDRICAL_SURFACE('',#1313,3.175);
#1315=ORIENTED_EDGE('',*,*,#1286,.T.);
#1316=ORIENTED_EDGE('',*,*,#550,.F.);
#1317=CARTESIAN_POINT('',(3.175,9.525,-31.75));
#1318=DIRECTION('',(0.,0.,-1.));
#1319=DIRECTION('',(-1.,0.,0.));
#1320=AXIS2_PLACEMENT_3D('',#1317,#1318,#1319);
#1321=CIRCLE('',#1320,3.175);
#1322=EDGE_CURVE('E596',#232,#541,#1321,.T.);
#1323=ORIENTED_EDGE('',*,*,#1322,.F.);
#1324=ORIENTED_EDGE('',*,*,#233,.F.);
#1325=EDGE_LOOP('',(#1315,#1316,#1323,#1324));
#1326=FACE_BOUND('',#1325,.T.);
#1327=ADVANCED_FACE('F701',(#1326),#1314,.T.);
#1328=CARTESIAN_POINT('',(95.25,9.525,-6.35));
#1329=DIRECTION('',(0.,-1.,0.));
#1330=DIRECTION('',(0.,0.,-1.));
#1331=AXIS2_PLACEMENT_3D('',#1328,#1329,#1330);
#1332=DEGENERATE_TOROIDAL_SURFACE('',#1331,3.175,3.175,.T.);
#1333=ORIENTED_EDGE('',*,*,#1304,.T.);
#1334=ORIENTED_EDGE('',*,*,#961,.F.);
#1335=CARTESIAN_POINT('',(98.425,9.525,-6.35));
#1336=DIRECTION('',(0.,0.,-1.));
#1337=DIRECTION('',(-1.,0.,0.));
#1338=AXIS2_PLACEMENT_3D('',#1335,#1336,#1337);
#1339=CIRCLE('',#1338,3.175);
#1340=EDGE_CURVE('E591',#507,#388,#1339,.T.);
#1341=ORIENTED_EDGE('',*,*,#1340,.F.);
#1342=ORIENTED_EDGE('',*,*,#508,.F.);
#1343=EDGE_LOOP('',(#1333,#1334,#1341,#1342));
#1344=FACE_BOUND('',#1343,.T.);
#1345=ADVANCED_FACE('F1131',(#1344),#1332,.T.);
#1346=CARTESIAN_POINT('',(6.35,9.525,-31.75));
#1347=DIRECTION('',(0.,-1.,0.));
#1348=DIRECTION('',(0.,0.,-1.));
#1349=AXIS2_PLACEMENT_3D('',#1346,#1347,#1348);
#1350=DEGENERATE_TOROIDAL_SURFACE('',#1349,3.175,3.175,.T.);
#1351=ORIENTED_EDGE('',*,*,#1322,.T.);
#1352=ORIENTED_EDGE('',*,*,#542,.F.);
#1353=CARTESIAN_POINT('',(6.35,9.525,-34.925));
#1354=DIRECTION('',(1.,0.,0.));
#1355=DIRECTION('',(0.,0.,-1.));
#1356=AXIS2_PLACEMENT_3D('',#1353,#1354,#1355);
#1357=CIRCLE('',#1356,3.175);
#1358=EDGE_CURVE('E595',#418,#532,#1357,.T.);
#1359=ORIENTED_EDGE('',*,*,#1358,.F.);
#1360=ORIENTED_EDGE('',*,*,#997,.F.);
#1361=EDGE_LOOP('',(#1351,#1352,#1359,#1360));
#1362=FACE_BOUND('',#1361,.T.);
#1363=ADVANCED_FACE('F708',(#1362),#1350,.T.);
#1364=CARTESIAN_POINT('',(98.425,9.525,-38.1));
#1365=DIRECTION('',(0.,0.,-1.));
#1366=DIRECTION('',(-1.,0.,0.));
#1367=AXIS2_PLACEMENT_3D('',#1364,#1365,#1366);
#1368=CYLINDRICAL_SURFACE('',#1367,3.175);
#1369=ORIENTED_EDGE('',*,*,#1340,.T.);
#1370=ORIENTED_EDGE('',*,*,#389,.F.);
#1371=CARTESIAN_POINT('',(98.425,9.525,-31.75));
#1372=DIRECTION('',(0.,0.,-1.));
#1373=DIRECTION('',(-1.,0.,0.));
#1374=AXIS2_PLACEMENT_3D('',#1371,#1372,#1373);
#1375=CIRCLE('',#1374,3.175);
#1376=EDGE_CURVE('E588',#515,#380,#1375,.T.);
#1377=ORIENTED_EDGE('',*,*,#1376,.F.);
#1378=ORIENTED_EDGE('',*,*,#516,.F.);
#1379=EDGE_LOOP('',(#1369,#1370,#1377,#1378));
#1380=FACE_BOUND('',#1379,.T.);
#1381=ADVANCED_FACE('F1155',(#1380),#1368,.T.);
#1382=CARTESIAN_POINT('',(0.,9.525,-34.925));
#1383=DIRECTION('',(-1.,0.,0.));
#1384=DIRECTION('',(0.,0.,1.));
#1385=AXIS2_PLACEMENT_3D('',#1382,#1383,#1384);
#1386=CYLINDRICAL_SURFACE('',#1385,3.175);
#1387=ORIENTED_EDGE('',*,*,#1358,.T.);
#1388=ORIENTED_EDGE('',*,*,#533,.F.);
#1389=CARTESIAN_POINT('',(95.25,9.525,-34.925));
#1390=DIRECTION('',(1.,0.,0.));
#1391=DIRECTION('',(0.,0.,-1.));
#1392=AXIS2_PLACEMENT_3D('',#1389,#1390,#1391);
#1393=CIRCLE('',#1392,3.175);
#1394=EDGE_CURVE('E590',#426,#524,#1393,.T.);
#1395=ORIENTED_EDGE('',*,*,#1394,.F.);
#1396=ORIENTED_EDGE('',*,*,#427,.F.);
#1397=EDGE_LOOP('',(#1387,#1388,#1395,#1396));
#1398=FACE_BOUND('',#1397,.T.);
#1399=ADVANCED_FACE('F713',(#1398),#1386,.T.);
#1400=CARTESIAN_POINT('',(95.25,9.525,-31.75));
#1401=DIRECTION('',(0.,-1.,0.));
#1402=DIRECTION('',(0.,0.,-1.));
#1403=AXIS2_PLACEMENT_3D('',#1400,#1401,#1402);
#1404=DEGENERATE_TOROIDAL_SURFACE('',#1403,3.175,3.175,.T.);
#1405=ORIENTED_EDGE('',*,*,#1376,.T.);
#1406=ORIENTED_EDGE('',*,*,#979,.F.);
#1407=ORIENTED_EDGE('',*,*,#1394,.T.);
#1408=ORIENTED_EDGE('',*,*,#525,.F.);
#1409=EDGE_LOOP('',(#1405,#1406,#1407,#1408));
#1410=FACE_BOUND('',#1409,.T.);
#1411=ADVANCED_FACE('F720',(#1410),#1404,.T.);
#1412=CLOSED_SHELL('',(#213,#244,#367,#407,#468,#616,#653,#693,#733,#785,#809,#829,#849,#861,
#883,#895,#907,#919,#931,#949,#967,#985,#1003,#1027,#1045,#1069,#1087,#1105,#1123,#1147,#1165,
#1183,#1201,#1219,#1237,#1255,#1273,#1291,#1309,#1327,#1345,#1363,#1381,#1399,#1411));
#1413=MANIFOLD_SOLID_BREP('B115',#1412);
#1414=ADVANCED_BREP_SHAPE_REPRESENTATION('',(#18,#1413),#14);
#1415=MANIFOLD_SURFACE_SHAPE_REPRESENTATION('',(#18,#60,#102,#144),#14);
#1416=SHAPE_REPRESENTATION('',(#18),#14);
#1417=SHAPE_DEFINITION_REPRESENTATION(#9,#1416);
#1418=SHAPE_REPRESENTATION_RELATIONSHIP('','',#1416,#1414);
#1419=SHAPE_REPRESENTATION_RELATIONSHIP('','',#1416,#1415);
ENDSEC;
END-ISO-10303-21;
